VERSION 5.7 ;
  NOWIREEXTENSIONATPIN ON ;
  DIVIDERCHAR "/" ;
  BUSBITCHARS "[]" ;
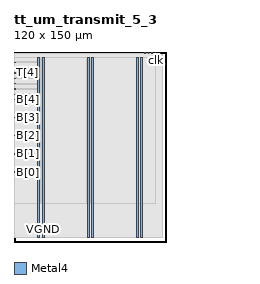
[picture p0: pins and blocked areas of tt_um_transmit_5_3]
MACRO tt_um_transmit_5_3
  CLASS BLOCK ;
  FOREIGN tt_um_transmit_5_3 ;
  ORIGIN 0.000 0.000 ;
  SIZE 120.000 BY 150.000 ;
  PIN B[0]
    DIRECTION OUTPUT ;
    USE SIGNAL ;
    ANTENNADIFFAREA 5.179600 ;
    PORT
      LAYER Metal4 ;
        RECT 0.000 55.100 1.000 55.400 ;
    END
  END B[0]
  PIN B[1]
    DIRECTION OUTPUT ;
    USE SIGNAL ;
    ANTENNADIFFAREA 5.801400 ;
    PORT
      LAYER Metal4 ;
        RECT 0.000 69.400 1.000 69.700 ;
    END
  END B[1]
  PIN B[2]
    DIRECTION OUTPUT ;
    USE SIGNAL ;
    ANTENNADIFFAREA 2.304600 ;
    PORT
      LAYER Metal4 ;
        RECT 0.000 83.700 1.000 84.000 ;
    END
  END B[2]
  PIN B[3]
    DIRECTION OUTPUT ;
    USE SIGNAL ;
    ANTENNADIFFAREA 5.179600 ;
    PORT
      LAYER Metal4 ;
        RECT 0.000 98.000 1.000 98.300 ;
    END
  END B[3]
  PIN B[4]
    DIRECTION OUTPUT ;
    USE SIGNAL ;
    ANTENNADIFFAREA 1.601600 ;
    PORT
      LAYER Metal4 ;
        RECT 0.000 112.300 1.000 112.600 ;
    END
  END B[4]
  PIN T[0]
    DIRECTION OUTPUT ;
    USE SIGNAL ;
    ANTENNADIFFAREA 2.932000 ;
    PORT
      LAYER Metal4 ;
        RECT 0.000 116.500 1.000 116.800 ;
    END
  END T[0]
  PIN T[1]
    DIRECTION OUTPUT ;
    USE SIGNAL ;
    ANTENNADIFFAREA 2.932000 ;
    PORT
      LAYER Metal4 ;
        RECT 0.000 120.700 1.000 121.000 ;
    END
  END T[1]
  PIN T[2]
    DIRECTION OUTPUT ;
    USE SIGNAL ;
    ANTENNADIFFAREA 2.932000 ;
    PORT
      LAYER Metal4 ;
        RECT 0.000 124.900 1.000 125.200 ;
    END
  END T[2]
  PIN T[3]
    DIRECTION OUTPUT ;
    USE SIGNAL ;
    ANTENNADIFFAREA 2.059200 ;
    PORT
      LAYER Metal4 ;
        RECT 0.000 129.100 1.000 129.400 ;
    END
  END T[3]
  PIN T[4]
    DIRECTION OUTPUT ;
    USE SIGNAL ;
    ANTENNADIFFAREA 2.932000 ;
    PORT
      LAYER Metal4 ;
        RECT 0.000 133.300 1.000 133.600 ;
    END
  END T[4]
  PIN T[5]
    DIRECTION OUTPUT ;
    USE SIGNAL ;
    ANTENNADIFFAREA 4.731200 ;
    PORT
      LAYER Metal4 ;
        RECT 0.000 137.500 1.000 137.800 ;
    END
  END T[5]
  PIN T[6]
    DIRECTION OUTPUT ;
    USE SIGNAL ;
    ANTENNADIFFAREA 4.731200 ;
    PORT
      LAYER Metal4 ;
        RECT 0.000 141.700 1.000 142.000 ;
    END
  END T[6]
  PIN VGND
    DIRECTION INOUT ;
    USE GROUND ;
    PORT
      LAYER Metal4 ;
        RECT 22.180 3.620 23.780 145.340 ;
    END
    PORT
      LAYER Metal4 ;
        RECT 61.050 3.620 62.650 145.340 ;
    END
    PORT
      LAYER Metal4 ;
        RECT 99.920 3.620 101.520 145.340 ;
    END
  END VGND
  PIN VPWR
    DIRECTION INOUT ;
    USE POWER ;
    PORT
      LAYER Metal4 ;
        RECT 18.880 3.620 20.480 145.340 ;
    END
    PORT
      LAYER Metal4 ;
        RECT 57.750 3.620 59.350 145.340 ;
    END
    PORT
      LAYER Metal4 ;
        RECT 96.620 3.620 98.220 145.340 ;
    END
  END VPWR
  PIN clk
    DIRECTION INPUT ;
    USE SIGNAL ;
    ANTENNAGATEAREA 4.738000 ;
    PORT
      LAYER Metal4 ;
        RECT 111.700 149.000 112.000 150.000 ;
    END
  END clk
  PIN enable
    DIRECTION INPUT ;
    USE SIGNAL ;
    ANTENNAGATEAREA 0.396000 ;
    PORT
      LAYER Metal4 ;
        RECT 103.420 149.000 103.720 150.000 ;
    END
  END enable
  PIN in
    DIRECTION INPUT ;
    USE SIGNAL ;
    ANTENNAGATEAREA 0.396000 ;
    PORT
      LAYER Metal4 ;
        RECT 106.180 149.000 106.480 150.000 ;
    END
  END in
  PIN rst_n
    DIRECTION INPUT ;
    USE SIGNAL ;
    ANTENNAGATEAREA 0.396000 ;
    PORT
      LAYER Metal4 ;
        RECT 108.940 149.000 109.240 150.000 ;
    END
  END rst_n
  OBS
      LAYER Nwell ;
        RECT 2.930 3.490 116.910 145.470 ;
      LAYER Metal1 ;
        RECT 3.360 3.620 116.480 145.340 ;
      LAYER Metal2 ;
        RECT 1.260 3.730 116.900 148.310 ;
      LAYER Metal3 ;
        RECT 0.090 3.780 116.950 148.260 ;
      LAYER Metal4 ;
        RECT 0.140 148.700 103.120 149.000 ;
        RECT 104.020 148.700 105.880 149.000 ;
        RECT 106.780 148.700 108.640 149.000 ;
        RECT 109.540 148.700 111.400 149.000 ;
        RECT 0.140 145.640 111.990 148.700 ;
        RECT 0.140 142.300 18.580 145.640 ;
        RECT 1.300 141.400 18.580 142.300 ;
        RECT 0.140 138.100 18.580 141.400 ;
        RECT 1.300 137.200 18.580 138.100 ;
        RECT 0.140 133.900 18.580 137.200 ;
        RECT 1.300 133.000 18.580 133.900 ;
        RECT 0.140 129.700 18.580 133.000 ;
        RECT 1.300 128.800 18.580 129.700 ;
        RECT 0.140 125.500 18.580 128.800 ;
        RECT 1.300 124.600 18.580 125.500 ;
        RECT 0.140 121.300 18.580 124.600 ;
        RECT 1.300 120.400 18.580 121.300 ;
        RECT 0.140 117.100 18.580 120.400 ;
        RECT 1.300 116.200 18.580 117.100 ;
        RECT 0.140 112.900 18.580 116.200 ;
        RECT 1.300 112.000 18.580 112.900 ;
        RECT 0.140 98.600 18.580 112.000 ;
        RECT 1.300 97.700 18.580 98.600 ;
        RECT 0.140 84.300 18.580 97.700 ;
        RECT 1.300 83.400 18.580 84.300 ;
        RECT 0.140 70.000 18.580 83.400 ;
        RECT 1.300 69.100 18.580 70.000 ;
        RECT 0.140 55.700 18.580 69.100 ;
        RECT 1.300 54.800 18.580 55.700 ;
        RECT 0.140 30.330 18.580 54.800 ;
        RECT 20.780 30.330 21.880 145.640 ;
        RECT 24.080 30.330 57.450 145.640 ;
        RECT 59.650 30.330 60.750 145.640 ;
        RECT 62.950 30.330 96.320 145.640 ;
        RECT 98.520 30.330 99.620 145.640 ;
        RECT 101.820 30.330 111.990 145.640 ;
  END
END tt_um_transmit_5_3
END LIBRARY

